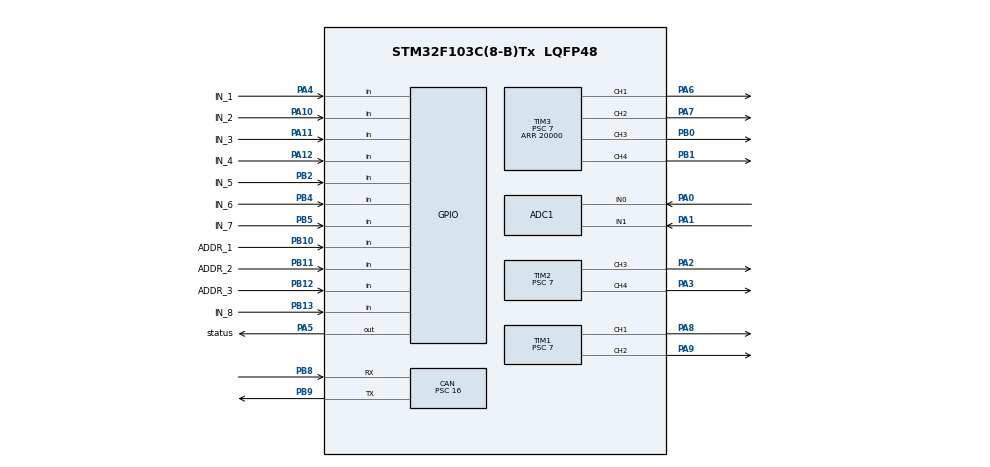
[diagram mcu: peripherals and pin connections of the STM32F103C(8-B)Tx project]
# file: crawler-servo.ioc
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ADC1.Channel-0\#ChannelRegularConversion=ADC_CHANNEL_0
ADC1.Channel-1\#ChannelRegularConversion=ADC_CHANNEL_1
ADC1.NbrOfConversion=2
ADC1.NbrOfConversionFlag=1
ADC1.Rank-0\#ChannelRegularConversion=1
ADC1.Rank-1\#ChannelRegularConversion=2
ADC1.SamplingTime-0\#ChannelRegularConversion=ADC_SAMPLETIME_1CYCLE_5
ADC1.SamplingTime-1\#ChannelRegularConversion=ADC_SAMPLETIME_1CYCLE_5
ADC1.master=1
CAN.CalculateBaudRate=500000
CAN.CalculateTimeBit=2000
CAN.CalculateTimeQuantum=666.6666666666666
CAN.Prescaler=16
Dma.ADC1.0.Direction=DMA_PERIPH_TO_MEMORY
Dma.ADC1.0.Instance=DMA1_Channel1
Dma.ADC1.0.MemDataAlignment=DMA_MDATAALIGN_WORD
Dma.ADC1.0.MemInc=DMA_MINC_ENABLE
Dma.ADC1.0.Mode=DMA_CIRCULAR
Dma.ADC1.0.PeriphDataAlignment=DMA_PDATAALIGN_HALFWORD
Dma.ADC1.0.PeriphInc=DMA_PINC_DISABLE
Dma.ADC1.0.Priority=DMA_PRIORITY_LOW
Dma.Request0=ADC1
Mcu.Family=STM32F1
Mcu.Name=STM32F103C(8-B)Tx
Mcu.Package=LQFP48
NVIC.DMA1_Channel1_IRQn=true\:0\:0\:false\:false\:true\:false\:true\:true
NVIC.PriorityGroup=NVIC_PRIORITYGROUP_4
NVIC.USB_LP_CAN1_RX0_IRQn=true\:0\:0\:false\:false\:true\:true\:true\:true
PA0-WKUP.Signal=ADCx_IN0
PA1.Signal=ADCx_IN1
PA10.GPIO_Label=IN_2
PA10.Signal=GPIO_Input
PA11.GPIO_Label=IN_3
PA11.Signal=GPIO_Input
PA12.GPIO_Label=IN_4
PA12.Signal=GPIO_Input
PA2.Signal=S_TIM2_CH3
PA3.Signal=S_TIM2_CH4
PA4.GPIO_Label=IN_1
PA4.Signal=GPIO_Input
PA5.GPIO_Label=status
PA5.Signal=GPIO_Output
PA6.Signal=S_TIM3_CH1
PA7.Signal=S_TIM3_CH2
PA8.Signal=S_TIM1_CH1
PA9.Signal=S_TIM1_CH2
PB0.Signal=S_TIM3_CH3
PB1.Signal=S_TIM3_CH4
PB10.GPIO_Label=ADDR_1
PB10.GPIO_PuPd=GPIO_PULLUP
PB10.Signal=GPIO_Input
PB11.GPIO_Label=ADDR_2
PB11.GPIO_PuPd=GPIO_PULLUP
PB11.Signal=GPIO_Input
PB12.GPIO_Label=ADDR_3
PB12.GPIO_PuPd=GPIO_PULLUP
PB12.Signal=GPIO_Input
PB13.GPIO_Label=IN_8
PB13.Signal=GPIO_Input
PB2.GPIO_Label=IN_5
PB2.Signal=GPIO_Input
PB4.GPIO_Label=IN_6
PB4.Signal=GPIO_Input
PB5.GPIO_Label=IN_7
PB5.Signal=GPIO_Input
PB8.Mode=CAN_Activate
PB8.Signal=CAN_RX
PB9.Mode=CAN_Activate
PB9.Signal=CAN_TX
ProjectManager.HeapSize=0x200
ProjectManager.StackSize=0x400
ProjectManager.TargetToolchain=Makefile
RCC.AHBFreq_Value=24000000
RCC.APB1Freq_Value=24000000
RCC.APB1TimFreq_Value=24000000
RCC.APB2Freq_Value=24000000
RCC.APB2TimFreq_Value=24000000
RCC.HCLKFreq_Value=24000000
RCC.PLLMUL=RCC_PLL_MUL6
RCC.SYSCLKFreq_VALUE=24000000
RCC.SYSCLKSource=RCC_SYSCLKSOURCE_PLLCLK
RCC.USBFreq_Value=24000000
SH.ADCx_IN0.0=ADC1_IN0,IN0
SH.ADCx_IN1.0=ADC1_IN1,IN1
SH.S_TIM1_CH1.0=TIM1_CH1,PWM Generation1 CH1
SH.S_TIM1_CH2.0=TIM1_CH2,PWM Generation2 CH2
SH.S_TIM2_CH3.0=TIM2_CH3,PWM Generation3 CH3
SH.S_TIM2_CH4.0=TIM2_CH4,PWM Generation4 CH4
SH.S_TIM3_CH1.0=TIM3_CH1,PWM Generation1 CH1
SH.S_TIM3_CH2.0=TIM3_CH2,PWM Generation2 CH2
SH.S_TIM3_CH3.0=TIM3_CH3,PWM Generation3 CH3
SH.S_TIM3_CH4.0=TIM3_CH4,PWM Generation4 CH4
TIM1.Channel-PWM\ Generation1\ CH1=TIM_CHANNEL_1
TIM1.Channel-PWM\ Generation2\ CH2=TIM_CHANNEL_2
TIM1.ClockDivision=TIM_CLOCKDIVISION_DIV1
TIM1.Period=20000
TIM1.Prescaler=7
TIM1.Pulse-PWM\ Generation1\ CH1=1500
TIM1.Pulse-PWM\ Generation2\ CH2=1500
TIM2.Channel-PWM\ Generation3\ CH3=TIM_CHANNEL_3
TIM2.Channel-PWM\ Generation4\ CH4=TIM_CHANNEL_4
TIM2.Period=20000
TIM2.Prescaler=7
TIM3.Channel-PWM\ Generation1\ CH1=TIM_CHANNEL_1
TIM3.Channel-PWM\ Generation2\ CH2=TIM_CHANNEL_2
TIM3.Channel-PWM\ Generation3\ CH3=TIM_CHANNEL_3
TIM3.Channel-PWM\ Generation4\ CH4=TIM_CHANNEL_4
TIM3.Period=20000
TIM3.Prescaler=7
VP_SYS_VS_ND.Mode=No_Debug
VP_TIM1_VS_ClockSourceINT.Mode=Internal
VP_TIM2_VS_ClockSourceINT.Mode=Internal
VP_TIM3_VS_ClockSourceINT.Mode=Internal
board=custom

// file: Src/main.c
/* USER CODE BEGIN Header */
/**
  ******************************************************************************
  * @file           : main.c
  * @brief          : Main program body
  ******************************************************************************
  * @attention
  *
  * Copyright (c) 2023 STMicroelectronics.
  * All rights reserved.
  *
  * This software is licensed under terms that can be found in the LICENSE file
  * in the root directory of this software component.
  * If no LICENSE file comes with this software, it is provided AS-IS.
  *
  ******************************************************************************
  */
/* USER CODE END Header */
#include "main.h"

/* USER CODE BEGIN PD */
#define BASE_CHANNEL_ID 0x010 //TODO: Read from DIP switches
#define N_CHANNELS 8
#define SERVO_CENTER 1500
#define SAFETY_TIMEOUT 2000
#define CAN_MESSAGES 2 //number of different messages to send over CAN bus

/* USER CODE END PD */

ADC_HandleTypeDef hadc1;
DMA_HandleTypeDef hdma_adc1;

CAN_HandleTypeDef hcan;

TIM_HandleTypeDef htim1;
TIM_HandleTypeDef htim2;
TIM_HandleTypeDef htim3;

/* USER CODE BEGIN PV */
//CAN bus
CAN_RxHeaderTypeDef rxHeader; //Transmit Header
CAN_TxHeaderTypeDef txHeader; //Receive Header
uint8_t canRX[8] = {0,0,0,0,0,0,0,0};  //Receive Buffer
CAN_FilterTypeDef canfil; //Filter
uint32_t canMailbox; //Mail box variable
uint32_t CANAddress;

//Servo
uint32_t servoLastUpdated[N_CHANNELS] = {0}; //timestamps for timeout

//ADC
uint32_t ADCResults[2] = {0,0}; //ADC results
/* USER CODE END PV */

void SystemClock_Config(void);
static void MX_GPIO_Init(void);
static void MX_DMA_Init(void);
static void MX_ADC1_Init(void);
static void MX_CAN_Init(void);
static void MX_TIM1_Init(void);
static void MX_TIM2_Init(void);
static void MX_TIM3_Init(void);
/* USER CODE BEGIN PFP */
void setServo(uint8_t channel, uint16_t value);

/* USER CODE END PFP */

int main(void)
{

  /* MCU Configuration--------------------------------------------------------*/

  /* Reset of all peripherals, Initializes the Flash interface and the Systick. */
  HAL_Init();

  /* Configure the system clock */
  SystemClock_Config();

  /* Initialize all configured peripherals */
  MX_GPIO_Init();
  MX_DMA_Init();
  MX_ADC1_Init();
  MX_CAN_Init();
  MX_TIM1_Init();
  MX_TIM2_Init();
  MX_TIM3_Init();
  /* USER CODE BEGIN 2 */

  //setup servos
  for(int i=0; i<N_CHANNELS; i++)
    setServo(i, SERVO_CENTER);
  /* USER CODE END 2 */

  /* Infinite loop */
  /* USER CODE BEGIN WHILE */
  uint32_t txMailbox;
  while (1)
  {
    HAL_GPIO_WritePin(status_GPIO_Port, status_Pin, GPIO_PIN_SET);

    //transmit status
    if (HAL_CAN_GetTxMailboxesFreeLevel(&hcan) > 0){
            //set address
            static uint8_t TXCounter = 0;
            uint8_t data[2] = {0};
            txHeader.StdId = CANAddress | 0x8 | (TXCounter & 0b111);

            //fetch correct data
            switch(TXCounter){
                case 0: //battery voltage
                    data[1] = ADCResults[0] & 0xff;
                    data[0] = (ADCResults[0]>>8) & 0xff;
                    break;
                case 1: //battery current
                    data[1] = ADCResults[1] & 0xff;
                    data[0] = (ADCResults[1]>>8) & 0xff;
                    break;
            }

            //send
            HAL_CAN_AddTxMessage(&hcan, &txHeader, data, &txMailbox);

            //next address
            TXCounter++;
            if (TXCounter > CAN_MESSAGES-1)
                TXCounter = 0;
    }

    HAL_ADC_Start_DMA(&hadc1, ADCResults, 2); // start adc in DMA mode

    //center any channel that hasn't been updated for a while
    for(int i=0; i<N_CHANNELS; i++){
        if ( (HAL_GetTick() - servoLastUpdated[i]) > SAFETY_TIMEOUT)
            setServo(i, SERVO_CENTER);
    }

    HAL_GPIO_WritePin(status_GPIO_Port, status_Pin, GPIO_PIN_RESET);
    HAL_Delay(1000/(CAN_MESSAGES*3));
    /* USER CODE END WHILE */

  }
}

void SystemClock_Config(void)
{
  RCC_OscInitTypeDef RCC_OscInitStruct = {0};
  RCC_ClkInitTypeDef RCC_ClkInitStruct = {0};
  RCC_PeriphCLKInitTypeDef PeriphClkInit = {0};

  /** Initializes the RCC Oscillators according to the specified parameters
  * in the RCC_OscInitTypeDef structure.
  */
  RCC_OscInitStruct.OscillatorType = RCC_OSCILLATORTYPE_HSI;
  RCC_OscInitStruct.HSIState = RCC_HSI_ON;
  RCC_OscInitStruct.HSICalibrationValue = RCC_HSICALIBRATION_DEFAULT;
  RCC_OscInitStruct.PLL.PLLState = RCC_PLL_NONE;
  if (HAL_RCC_OscConfig(&RCC_OscInitStruct) != HAL_OK)
  {
    Error_Handler();
  }

  /** Initializes the CPU, AHB and APB buses clocks
  */
  RCC_ClkInitStruct.ClockType = RCC_CLOCKTYPE_HCLK|RCC_CLOCKTYPE_SYSCLK
                              |RCC_CLOCKTYPE_PCLK1|RCC_CLOCKTYPE_PCLK2;
  RCC_ClkInitStruct.SYSCLKSource = RCC_SYSCLKSOURCE_HSI;
  RCC_ClkInitStruct.AHBCLKDivider = RCC_SYSCLK_DIV1;
  RCC_ClkInitStruct.APB1CLKDivider = RCC_HCLK_DIV1;
  RCC_ClkInitStruct.APB2CLKDivider = RCC_HCLK_DIV1;

  if (HAL_RCC_ClockConfig(&RCC_ClkInitStruct, FLASH_LATENCY_0) != HAL_OK)
  {
    Error_Handler();
  }
  PeriphClkInit.PeriphClockSelection = RCC_PERIPHCLK_ADC;
  PeriphClkInit.AdcClockSelection = RCC_ADCPCLK2_DIV2;
  if (HAL_RCCEx_PeriphCLKConfig(&PeriphClkInit) != HAL_OK)
  {
    Error_Handler();
  }
}

static void MX_ADC1_Init(void)
{

  ADC_ChannelConfTypeDef sConfig = {0};

  /** Common config
  */
  hadc1.Instance = ADC1;
  hadc1.Init.ScanConvMode = ADC_SCAN_ENABLE;
  hadc1.Init.ContinuousConvMode = DISABLE;
  hadc1.Init.DiscontinuousConvMode = DISABLE;
  hadc1.Init.ExternalTrigConv = ADC_SOFTWARE_START;
  hadc1.Init.DataAlign = ADC_DATAALIGN_RIGHT;
  hadc1.Init.NbrOfConversion = 2;
  if (HAL_ADC_Init(&hadc1) != HAL_OK)
  {
    Error_Handler();
  }

  /** Configure Regular Channel
  */
  sConfig.Channel = ADC_CHANNEL_0;
  sConfig.Rank = ADC_REGULAR_RANK_1;
  sConfig.SamplingTime = ADC_SAMPLETIME_1CYCLE_5;
  if (HAL_ADC_ConfigChannel(&hadc1, &sConfig) != HAL_OK)
  {
    Error_Handler();
  }

  /** Configure Regular Channel
  */
  sConfig.Channel = ADC_CHANNEL_1;
  sConfig.Rank = ADC_REGULAR_RANK_2;
  if (HAL_ADC_ConfigChannel(&hadc1, &sConfig) != HAL_OK)
  {
    Error_Handler();
  }

}

static void MX_CAN_Init(void)
{

  hcan.Instance = CAN1;
  hcan.Init.Prescaler = 4;
  hcan.Init.Mode = CAN_MODE_NORMAL;
  hcan.Init.SyncJumpWidth = CAN_SJW_1TQ;
  hcan.Init.TimeSeg1 = CAN_BS1_2TQ;
  hcan.Init.TimeSeg2 = CAN_BS2_1TQ;
  hcan.Init.TimeTriggeredMode = DISABLE;
  hcan.Init.AutoBusOff = DISABLE;
  hcan.Init.AutoWakeUp = DISABLE;
  hcan.Init.AutoRetransmission = DISABLE;
  hcan.Init.ReceiveFifoLocked = DISABLE;
  hcan.Init.TransmitFifoPriority = DISABLE;
  if (HAL_CAN_Init(&hcan) != HAL_OK)
  {
    Error_Handler();
  }
  /* USER CODE BEGIN CAN_Init 2 */
  txHeader.DLC = 2;
  txHeader.IDE = CAN_ID_STD;
  txHeader.RTR = CAN_RTR_DATA;
  txHeader.StdId =  CANAddress | 0x8;
l txHeader.ExtId = 0x00;
  txHeader.TransmitGlobalTime = DISABLE;
  canfil.FilterBank = 0;
  canfil.FilterMode = CAN_FILTERMODE_IDMASK;
  canfil.FilterFIFOAssignment = CAN_RX_FIFO0;
  canfil.FilterIdHigh = CANAddress << 5;
  canfil.FilterIdLow = 0;
  canfil.FilterMaskIdHigh = 0x7f8<<5;
  canfil.FilterMaskIdLow = 0;
  canfil.FilterScale = CAN_FILTERSCALE_32BIT;
  canfil.FilterActivation = ENABLE;
  canfil.SlaveStartFilterBank = 14;
  HAL_CAN_ConfigFilter(&hcan,&canfil); //Initialize CAN Filter
  HAL_CAN_Start(&hcan); //Initialize CAN Bus
  HAL_CAN_ActivateNotification(&hcan,CAN_IT_RX_FIFO0_MSG_PENDING);// Initialize CAN Bus Rx Interrupt
  /* USER CODE END CAN_Init 2 */

}

static void MX_TIM1_Init(void)
{

  TIM_ClockConfigTypeDef sClockSourceConfig = {0};
  TIM_MasterConfigTypeDef sMasterConfig = {0};
  TIM_OC_InitTypeDef sConfigOC = {0};
  TIM_BreakDeadTimeConfigTypeDef sBreakDeadTimeConfig = {0};

  htim1.Instance = TIM1;
  htim1.Init.Prescaler = 7;
  htim1.Init.CounterMode = TIM_COUNTERMODE_UP;
  htim1.Init.Period = 20000;
  htim1.Init.ClockDivision = TIM_CLOCKDIVISION_DIV1;
  htim1.Init.RepetitionCounter = 0;
  htim1.Init.AutoReloadPreload = TIM_AUTORELOAD_PRELOAD_DISABLE;
  if (HAL_TIM_Base_Init(&htim1) != HAL_OK)
  {
    Error_Handler();
  }
  sClockSourceConfig.ClockSource = TIM_CLOCKSOURCE_INTERNAL;
  if (HAL_TIM_ConfigClockSource(&htim1, &sClockSourceConfig) != HAL_OK)
  {
    Error_Handler();
  }
  if (HAL_TIM_PWM_Init(&htim1) != HAL_OK)
  {
    Error_Handler();
  }
  sMasterConfig.MasterOutputTrigger = TIM_TRGO_RESET;
  sMasterConfig.MasterSlaveMode = TIM_MASTERSLAVEMODE_DISABLE;
  if (HAL_TIMEx_MasterConfigSynchronization(&htim1, &sMasterConfig) != HAL_OK)
  {
    Error_Handler();
  }
  sConfigOC.OCMode = TIM_OCMODE_PWM1;
  sConfigOC.Pulse = 1500;
  sConfigOC.OCPolarity = TIM_OCPOLARITY_HIGH;
  sConfigOC.OCNPolarity = TIM_OCNPOLARITY_HIGH;
  sConfigOC.OCFastMode = TIM_OCFAST_DISABLE;
  sConfigOC.OCIdleState = TIM_OCIDLESTATE_RESET;
  sConfigOC.OCNIdleState = TIM_OCNIDLESTATE_RESET;
  if (HAL_TIM_PWM_ConfigChannel(&htim1, &sConfigOC, TIM_CHANNEL_1) != HAL_OK)
  {
    Error_Handler();
  }
  if (HAL_TIM_PWM_ConfigChannel(&htim1, &sConfigOC, TIM_CHANNEL_2) != HAL_OK)
  {
    Error_Handler();
  }
  sBreakDeadTimeConfig.OffStateRunMode = TIM_OSSR_DISABLE;
  sBreakDeadTimeConfig.OffStateIDLEMode = TIM_OSSI_DISABLE;
  sBreakDeadTimeConfig.LockLevel = TIM_LOCKLEVEL_OFF;
  sBreakDeadTimeConfig.DeadTime = 0;
  sBreakDeadTimeConfig.BreakState = TIM_BREAK_DISABLE;
  sBreakDeadTimeConfig.BreakPolarity = TIM_BREAKPOLARITY_HIGH;
  sBreakDeadTimeConfig.AutomaticOutput = TIM_AUTOMATICOUTPUT_DISABLE;
  if (HAL_TIMEx_ConfigBreakDeadTime(&htim1, &sBreakDeadTimeConfig) != HAL_OK)
  {
    Error_Handler();
  }
  /* USER CODE BEGIN TIM1_Init 2 */
  HAL_TIM_Base_Start_IT(&htim1);
  HAL_TIM_PWM_Start(&htim1, TIM_CHANNEL_1);
  HAL_TIM_PWM_Start(&htim1, TIM_CHANNEL_2);
  /* USER CODE END TIM1_Init 2 */
  HAL_TIM_MspPostInit(&htim1);

}

static void MX_TIM2_Init(void)
{

  TIM_ClockConfigTypeDef sClockSourceConfig = {0};
  TIM_MasterConfigTypeDef sMasterConfig = {0};
  TIM_OC_InitTypeDef sConfigOC = {0};

  htim2.Instance = TIM2;
  htim2.Init.Prescaler = 7;
  htim2.Init.CounterMode = TIM_COUNTERMODE_UP;
  htim2.Init.Period = 20000;
  htim2.Init.ClockDivision = TIM_CLOCKDIVISION_DIV1;
  htim2.Init.AutoReloadPreload = TIM_AUTORELOAD_PRELOAD_DISABLE;
  if (HAL_TIM_Base_Init(&htim2) != HAL_OK)
  {
    Error_Handler();
  }
  sClockSourceConfig.ClockSource = TIM_CLOCKSOURCE_INTERNAL;
  if (HAL_TIM_ConfigClockSource(&htim2, &sClockSourceConfig) != HAL_OK)
  {
    Error_Handler();
  }
  if (HAL_TIM_PWM_Init(&htim2) != HAL_OK)
  {
    Error_Handler();
  }
  sMasterConfig.MasterOutputTrigger = TIM_TRGO_RESET;
  sMasterConfig.MasterSlaveMode = TIM_MASTERSLAVEMODE_DISABLE;
  if (HAL_TIMEx_MasterConfigSynchronization(&htim2, &sMasterConfig) != HAL_OK)
  {
    Error_Handler();
  }
  sConfigOC.OCMode = TIM_OCMODE_PWM1;
  sConfigOC.Pulse = 0;
  sConfigOC.OCPolarity = TIM_OCPOLARITY_HIGH;
  sConfigOC.OCFastMode = TIM_OCFAST_DISABLE;
  if (HAL_TIM_PWM_ConfigChannel(&htim2, &sConfigOC, TIM_CHANNEL_3) != HAL_OK)
  {
    Error_Handler();
  }
  if (HAL_TIM_PWM_ConfigChannel(&htim2, &sConfigOC, TIM_CHANNEL_4) != HAL_OK)
  {
    Error_Handler();
  }
  /* USER CODE BEGIN TIM2_Init 2 */
  HAL_TIM_Base_Start_IT(&htim2);
  HAL_TIM_PWM_Start(&htim2, TIM_CHANNEL_3);
  HAL_TIM_PWM_Start(&htim2, TIM_CHANNEL_4);
  /* USER CODE END TIM2_Init 2 */
  HAL_TIM_MspPostInit(&htim2);

}

static void MX_TIM3_Init(void)
{

  TIM_ClockConfigTypeDef sClockSourceConfig = {0};
  TIM_MasterConfigTypeDef sMasterConfig = {0};
  TIM_OC_InitTypeDef sConfigOC = {0};

  htim3.Instance = TIM3;
  htim3.Init.Prescaler = 7;
  htim3.Init.CounterMode = TIM_COUNTERMODE_UP;
  htim3.Init.Period = 20000;
  htim3.Init.ClockDivision = TIM_CLOCKDIVISION_DIV1;
  htim3.Init.AutoReloadPreload = TIM_AUTORELOAD_PRELOAD_DISABLE;
  if (HAL_TIM_Base_Init(&htim3) != HAL_OK)
  {
    Error_Handler();
  }
  sClockSourceConfig.ClockSource = TIM_CLOCKSOURCE_INTERNAL;
  if (HAL_TIM_ConfigClockSource(&htim3, &sClockSourceConfig) != HAL_OK)
  {
    Error_Handler();
  }
  if (HAL_TIM_PWM_Init(&htim3) != HAL_OK)
  {
    Error_Handler();
  }
  sMasterConfig.MasterOutputTrigger = TIM_TRGO_RESET;
  sMasterConfig.MasterSlaveMode = TIM_MASTERSLAVEMODE_DISABLE;
  if (HAL_TIMEx_MasterConfigSynchronization(&htim3, &sMasterConfig) != HAL_OK)
  {
    Error_Handler();
  }
  sConfigOC.OCMode = TIM_OCMODE_PWM1;
  sConfigOC.Pulse = 0;
  sConfigOC.OCPolarity = TIM_OCPOLARITY_HIGH;
  sConfigOC.OCFastMode = TIM_OCFAST_DISABLE;
  if (HAL_TIM_PWM_ConfigChannel(&htim3, &sConfigOC, TIM_CHANNEL_1) != HAL_OK)
  {
    Error_Handler();
  }
  if (HAL_TIM_PWM_ConfigChannel(&htim3, &sConfigOC, TIM_CHANNEL_2) != HAL_OK)
  {
    Error_Handler();
  }
  if (HAL_TIM_PWM_ConfigChannel(&htim3, &sConfigOC, TIM_CHANNEL_3) != HAL_OK)
  {
    Error_Handler();
  }
  if (HAL_TIM_PWM_ConfigChannel(&htim3, &sConfigOC, TIM_CHANNEL_4) != HAL_OK)
  {
    Error_Handler();
  }
  /* USER CODE BEGIN TIM3_Init 2 */
  HAL_TIM_Base_Start_IT(&htim3);
  HAL_TIM_PWM_Start(&htim3, TIM_CHANNEL_1);
  HAL_TIM_PWM_Start(&htim3, TIM_CHANNEL_2);
  HAL_TIM_PWM_Start(&htim3, TIM_CHANNEL_3);
  HAL_TIM_PWM_Start(&htim3, TIM_CHANNEL_4);
  /* USER CODE END TIM3_Init 2 */
  HAL_TIM_MspPostInit(&htim3);

}

static void MX_DMA_Init(void)
{

  /* DMA controller clock enable */
  __HAL_RCC_DMA1_CLK_ENABLE();

  /* DMA interrupt init */
  /* DMA1_Channel1_IRQn interrupt configuration */
  HAL_NVIC_SetPriority(DMA1_Channel1_IRQn, 0, 0);
  HAL_NVIC_EnableIRQ(DMA1_Channel1_IRQn);

}

static void MX_GPIO_Init(void)
{
  GPIO_InitTypeDef GPIO_InitStruct = {0};

  /* GPIO Ports Clock Enable */
  __HAL_RCC_GPIOD_CLK_ENABLE();
  __HAL_RCC_GPIOA_CLK_ENABLE();
  __HAL_RCC_GPIOB_CLK_ENABLE();

  /*Configure GPIO pin Output Level */
  HAL_GPIO_WritePin(status_GPIO_Port, status_Pin, GPIO_PIN_RESET);

  /*Configure GPIO pin : status_Pin */
  GPIO_InitStruct.Pin = status_Pin;
  GPIO_InitStruct.Mode = GPIO_MODE_OUTPUT_PP;
  GPIO_InitStruct.Pull = GPIO_NOPULL;
  GPIO_InitStruct.Speed = GPIO_SPEED_FREQ_LOW;
  HAL_GPIO_Init(status_GPIO_Port, &GPIO_InitStruct);

  /*Configure GPIO pins : PB10 PB11 PB12 */
  GPIO_InitStruct.Pin = GPIO_PIN_10|GPIO_PIN_11|GPIO_PIN_12;
  GPIO_InitStruct.Mode = GPIO_MODE_INPUT;
  GPIO_InitStruct.Pull = GPIO_PULLUP;
  HAL_GPIO_Init(GPIOB, &GPIO_InitStruct);

/* USER CODE BEGIN MX_GPIO_Init_2 */
  CANAddress = (
    HAL_GPIO_ReadPin(GPIOB, GPIO_PIN_10) << 0 |
    HAL_GPIO_ReadPin(GPIOB, GPIO_PIN_11) << 1 |
    HAL_GPIO_ReadPin(GPIOB, GPIO_PIN_12) << 2
    ) << 4;

/* USER CODE END MX_GPIO_Init_2 */
}

/* USER CODE BEGIN 4 */
//interrupt for received CAN frame
void HAL_CAN_RxFifo0MsgPendingCallback(CAN_HandleTypeDef *hcan1)
{
    //inform user of received data
    HAL_GPIO_WritePin(status_GPIO_Port, status_Pin, GPIO_PIN_SET);

    //get CAN bus message to canRX buffer
    HAL_CAN_GetRxMessage(hcan1, CAN_RX_FIFO0, &rxHeader, canRX);

    //match arbitration ID to pwm channel
    uint8_t channel = rxHeader.StdId & 0x7;

    //combine bytes
    uint16_t value = canRX[0]<<8 | canRX[1];

    setServo(channel, value);
}

void setServo(uint8_t channel, uint16_t value){
    //match to timer channels
    switch(channel){
        case 0:
            TIM1->CCR1 = value; //PA8
            break;
        case 1:
            TIM1->CCR2 = value; //PA9
            break;
        case 2:
            TIM2->CCR3 = value; //PA2
            break;
        case 3:
            TIM2->CCR4 = value; //PA3
            break;
        case 4:
            TIM3->CCR1 = value; //PA6
            break;
        case 5:
            TIM3->CCR2 = value; //PA7
            break;
        case 6:
            TIM3->CCR3 = value; //PB0
            break;
        case 7:
            TIM3->CCR4 = value; //PB1
            break;
    }
    servoLastUpdated[channel] = HAL_GetTick(); //update for timeout
}

/* USER CODE END 4 */

void Error_Handler(void)
{
  /* USER CODE BEGIN Error_Handler_Debug */
  /* User can add his own implementation to report the HAL error return state */
  __disable_irq();

  //set all channels to middle position
  for(uint8_t channel = 0; channel < N_CHANNELS; channel++)
    setServo(channel, SERVO_CENTER);

  while (1)
  {
    HAL_GPIO_TogglePin(status_GPIO_Port, status_Pin);
    HAL_Delay(1000);
  }
  /* USER CODE END Error_Handler_Debug */
}
